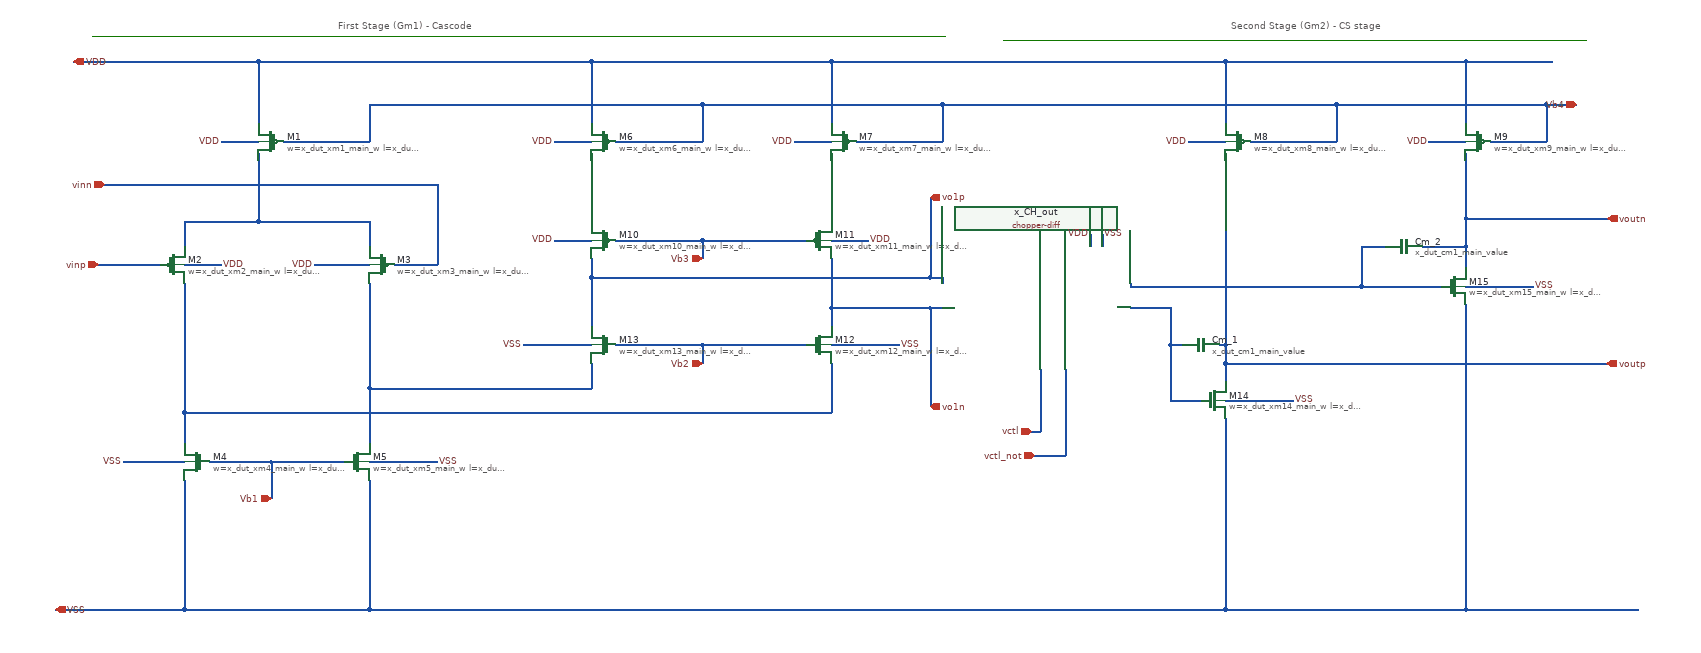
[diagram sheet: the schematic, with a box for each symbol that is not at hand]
v {xschem version=3.4.5 file_version=1.2
}
G {}
K {}
V {}
S {}
E {}
L 4 1600 -1055 2545 -1055 {}
L 4 120 -1060 1505 -1060 {}
T {First Stage (Gm1) - Cascode} 520 -1090 0 0 0.4 0.4 {}
T {Second Stage (Gm2) - CS stage} 1970 -1090 0 0 0.4 0.4 {}
N 270 -760 390 -760 {
lab=#net1}
N 270 -760 270 -720 {
lab=#net1}
N 390 -760 570 -760 {
lab=#net1}
N 570 -760 570 -720 {
lab=#net1}
N 390 -870 390 -760 {
lab=#net1}
N 610 -690 680 -690 {
lab=vinn}
N 680 -820 680 -690 {
lab=vinn}
N 140 -820 680 -820 {
lab=vinn}
N 130 -690 230 -690 {
lab=vinp}
N 270 -690 330 -690 {
lab=VDD}
N 480 -690 570 -690 {
lab=VDD}
N 330 -890 390 -890 {
lab=VDD}
N 430 -890 570 -890 {
lab=Vb4}
N 1320 -1020 1960 -1020 {
lab=VDD}
N 2350 -130 2630 -130 {
lab=VSS}
N 270 -450 270 -400 {
lab=#net2}
N 390 -1020 390 -920 {
lab=VDD}
N 90 -1020 390 -1020 {
lab=VDD}
N 570 -490 570 -400 {
lab=#net3}
N 410 -370 530 -370 {
lab=Vb1}
N 270 -340 270 -130 {
lab=VSS}
N 60 -130 270 -130 {
lab=VSS}
N 570 -340 570 -130 {
lab=VSS}
N 270 -130 570 -130 {
lab=VSS}
N 170 -370 270 -370 {
lab=VSS}
N 570 -370 680 -370 {
lab=VSS}
N 930 -870 930 -760 {
lab=#net4}
N 870 -890 930 -890 {
lab=VDD}
N 970 -890 1110 -890 {
lab=Vb4}
N 930 -1020 930 -920 {
lab=VDD}
N 390 -1020 930 -1020 {
lab=VDD}
N 1320 -870 1320 -760 {
lab=#net5}
N 1260 -890 1320 -890 {
lab=VDD}
N 1360 -890 1500 -890 {
lab=Vb4}
N 1320 -1020 1320 -920 {
lab=VDD}
N 930 -1020 1320 -1020 {
lab=VDD}
N 1960 -530 1960 -500 {
lab=voutp}
N 1900 -890 1960 -890 {
lab=VDD}
N 2000 -890 2140 -890 {
lab=Vb4}
N 1960 -1020 1960 -920 {
lab=VDD}
N 2290 -890 2350 -890 {
lab=VDD}
N 2480 -950 2530 -950 {
lab=Vb4}
N 2350 -1020 2350 -920 {
lab=VDD}
N 1960 -1020 2350 -1020 {
lab=VDD}
N 2350 -1020 2490 -1020 {
lab=VDD}
N 2480 -950 2480 -890 {
lab=Vb4}
N 2390 -890 2480 -890 {
lab=Vb4}
N 2140 -950 2480 -950 {
lab=Vb4}
N 2140 -950 2140 -890 {
lab=Vb4}
N 1500 -950 2140 -950 {
lab=Vb4}
N 1500 -950 1500 -890 {
lab=Vb4}
N 1110 -950 1500 -950 {
lab=Vb4}
N 1110 -950 1110 -890 {
lab=Vb4}
N 570 -950 1110 -950 {
lab=Vb4}
N 570 -950 570 -890 {
lab=Vb4}
N 870 -730 930 -730 {
lab=VDD}
N 1320 -730 1380 -730 {
lab=VDD}
N 1110 -730 1280 -730 {
lab=Vb3}
N 1320 -560 1430 -560 {
lab=VSS}
N 820 -560 930 -560 {
lab=VSS}
N 1320 -620 1320 -590 {
lab=vo1n}
N 930 -670 930 -590 {
lab=VDD}
N 1110 -560 1280 -560 {
lab=Vb2}
N 1320 -530 1320 -450 {
lab=#net2}
N 270 -450 1320 -450 {
lab=#net2}
N 270 -660 270 -450 {
lab=#net2}
N 930 -530 930 -490 {
lab=#net3}
N 570 -490 930 -490 {
lab=#net3}
N 570 -660 570 -490 {
lab=#net3}
N 410 -370 410 -310 {
lab=Vb1}
N 310 -370 410 -370 {
lab=Vb1}
N 1110 -560 1110 -530 {
lab=Vb2}
N 970 -560 1110 -560 {
lab=Vb2}
N 1110 -730 1110 -700 {
lab=Vb3}
N 970 -730 1110 -730 {
lab=Vb3}
N 1480 -620 1500 -620 {
lab=vo1n}
N 1320 -700 1320 -620 {
lab=vo1n}
N 1480 -670 1500 -670 {
lab=VDD}
N 930 -700 930 -670 {
lab=VDD}
N 1960 -470 2070 -470 {
lab=VSS}
N 2350 -655 2460 -655 {
lab=VSS}
N 1960 -130 2350 -130 {
lab=VSS}
N 1960 -440 1960 -130 {
lab=VSS}
N 570 -130 1960 -130 {
lab=VSS}
N 1870 -470 1920 -470 {
lab=#net6}
N 1870 -560 1870 -470 {
lab=#net6}
N 1805 -620 1870 -620 {
lab=#net6}
N 1870 -560 1890 -560 {
lab=#net6}
N 1870 -620 1870 -560 {
lab=#net6}
N 1950 -560 1960 -560 {
lab=voutp}
N 1960 -870 1960 -560 {
lab=voutp}
N 1805 -655 2180 -655 {
lab=#net7}
N 2180 -720 2180 -655 {
lab=#net7}
N 2180 -655 2310 -655 {
lab=#net7}
N 2180 -720 2220 -720 {
lab=#net7}
N 2280 -720 2350 -720 {
lab=voutn}
N 2350 -765 2350 -720 {
lab=voutn}
N 2350 -765 2580 -765 {
lab=voutn}
N 1960 -530 2580 -530 {
lab=voutp}
N 1960 -560 1960 -530 {
lab=voutp}
N 1500 -670 1500 -660 {
lab=VDD}
N 1805 -660 1805 -655 {
lab=#net7}
N 1660 -520 1660 -420 {
lab=vctl}
N 1645 -420 1660 -420 {
lab=vctl}
N 1650 -380 1700 -380 {
lab=vctl_not}
N 1700 -520 1700 -380 {
lab=vctl_not}
N 1740 -740 1740 -720 {
lab=VDD}
N 1760 -720 1760 -740 {
lab=VSS}
N 2350 -870 2350 -765 {
lab=voutn}
N 2350 -720 2350 -685 {
lab=voutn}
N 2350 -625 2350 -130 {
lab=VSS}
N 930 -670 1480 -670 {
lab=VDD}
N 1480 -620 1480 -460 {
lab=vo1n}
N 1320 -620 1480 -620 {
lab=vo1n}
N 1480 -800 1480 -670 {
lab=VDD}
C {devices/title.sym} 190 -70 0 0 {name=l5 author="Copyright 2026 MacAnalog Research Group"}
C {iopin.sym} 90 -1020 0 1 {name=p1 lab=VDD}
C {iopin.sym} 60 -130 0 1 {name=p5 lab=VSS}
C {sg13g2_pr/sg13_lv_pmos.sym} 410 -890 0 1 {name=M1
l=x_dut_xm1_main_l
w=x_dut_xm1_main_w
ng=1
m=1
model=sg13_lv_pmos
spiceprefix=X
}
C {sg13g2_pr/sg13_lv_pmos.sym} 250 -690 0 0 {name=M2
l=x_dut_xm2_main_l
w=x_dut_xm2_main_w
ng=1
m=1
model=sg13_lv_pmos
spiceprefix=X
}
C {sg13g2_pr/sg13_lv_pmos.sym} 590 -690 0 1 {name=M3
l=x_dut_xm3_main_l
w=x_dut_xm3_main_w
ng=1
m=1
model=sg13_lv_pmos
spiceprefix=X
}
C {iopin.sym} 2530 -950 0 0 {name=p2 lab=Vb4}
C {ipin.sym} 130 -690 0 0 {name=p3 lab=vinp}
C {ipin.sym} 140 -820 0 0 {name=p4 lab=vinn}
C {lab_pin.sym} 330 -690 0 1 {name=p8 sig_type=std_logic lab=VDD}
C {lab_pin.sym} 480 -690 0 0 {name=p9 sig_type=std_logic lab=VDD}
C {lab_pin.sym} 330 -890 0 0 {name=p10 sig_type=std_logic lab=VDD}
C {sg13g2_pr/sg13_lv_nmos.sym} 290 -370 0 1 {name=M4
l=x_dut_xm4_main_l
w=x_dut_xm4_main_w
ng=1
m=1
model=sg13_lv_nmos
spiceprefix=X
}
C {sg13g2_pr/sg13_lv_nmos.sym} 550 -370 0 0 {name=M5
l=x_dut_xm5_main_l
w=x_dut_xm5_main_w
ng=1
m=1
model=sg13_lv_nmos
spiceprefix=X
}
C {lab_pin.sym} 680 -370 0 1 {name=p6 sig_type=std_logic lab=VSS}
C {lab_pin.sym} 170 -370 0 0 {name=p7 sig_type=std_logic lab=VSS}
C {sg13g2_pr/sg13_lv_pmos.sym} 950 -890 0 1 {name=M6
l=x_dut_xm6_main_l
w=x_dut_xm6_main_w
ng=1
m=1
model=sg13_lv_pmos
spiceprefix=X
}
C {lab_pin.sym} 870 -890 0 0 {name=p11 sig_type=std_logic lab=VDD}
C {sg13g2_pr/sg13_lv_pmos.sym} 1340 -890 0 1 {name=M7
l=x_dut_xm7_main_l
w=x_dut_xm7_main_w
ng=1
m=1
model=sg13_lv_pmos
spiceprefix=X
}
C {lab_pin.sym} 1260 -890 0 0 {name=p12 sig_type=std_logic lab=VDD}
C {sg13g2_pr/sg13_lv_pmos.sym} 1980 -890 0 1 {name=M8
l=x_dut_xm8_main_l
w=x_dut_xm8_main_w
ng=1
m=1
model=sg13_lv_pmos
spiceprefix=X
}
C {lab_pin.sym} 1900 -890 0 0 {name=p13 sig_type=std_logic lab=VDD}
C {sg13g2_pr/sg13_lv_pmos.sym} 2370 -890 0 1 {name=M9
l=x_dut_xm9_main_l
w=x_dut_xm9_main_w
ng=1
m=1
model=sg13_lv_pmos
spiceprefix=X
}
C {lab_pin.sym} 2290 -890 0 0 {name=p14 sig_type=std_logic lab=VDD}
C {sg13g2_pr/sg13_lv_pmos.sym} 950 -730 0 1 {name=M10
l=x_dut_xm10_main_l
w=x_dut_xm10_main_w
ng=1
m=1
model=sg13_lv_pmos
spiceprefix=X
}
C {lab_pin.sym} 870 -730 0 0 {name=p15 sig_type=std_logic lab=VDD}
C {sg13g2_pr/sg13_lv_pmos.sym} 1300 -730 0 0 {name=M11
l=x_dut_xm11_main_l
w=x_dut_xm11_main_w
ng=1
m=1
model=sg13_lv_pmos
spiceprefix=X
}
C {lab_pin.sym} 1380 -730 0 1 {name=p16 sig_type=std_logic lab=VDD}
C {sg13g2_pr/sg13_lv_nmos.sym} 1300 -560 0 0 {name=M12
l=x_dut_xm12_main_l
w=x_dut_xm12_main_w
ng=1
m=1
model=sg13_lv_nmos
spiceprefix=X
}
C {lab_pin.sym} 1430 -560 0 1 {name=p17 sig_type=std_logic lab=VSS}
C {sg13g2_pr/sg13_lv_nmos.sym} 950 -560 0 1 {name=M13
l=x_dut_xm13_main_l
w=x_dut_xm13_main_w
ng=1
m=1
model=sg13_lv_nmos
spiceprefix=X
}
C {lab_pin.sym} 820 -560 0 0 {name=p18 sig_type=std_logic lab=VSS}
C {iopin.sym} 1110 -700 0 0 {name=p19 lab=Vb3}
C {iopin.sym} 1110 -530 0 0 {name=p20 lab=Vb2}
C {iopin.sym} 410 -310 0 0 {name=p21 lab=Vb1}
C {shared/chopper-diff.sym} 1520 -540 0 0 {name=x_CH_out}
C {sg13g2_pr/sg13_lv_nmos.sym} 1940 -470 0 0 {name=M14
l=x_dut_xm14_main_l
w=x_dut_xm14_main_w
ng=1
m=1
model=sg13_lv_nmos
spiceprefix=X
}
C {lab_pin.sym} 2070 -470 0 1 {name=p22 sig_type=std_logic lab=VSS}
C {sg13g2_pr/sg13_lv_nmos.sym} 2330 -655 0 0 {name=M15
l=x_dut_xm15_main_l
w=x_dut_xm15_main_w
ng=1
m=1
model=sg13_lv_nmos
spiceprefix=X
}
C {lab_pin.sym} 2460 -655 0 1 {name=p23 sig_type=std_logic lab=VSS}
C {capa.sym} 1920 -560 3 0 {name=Cm_1
m=1
value=x_dut_cm1_main_value
footprint=1206
device="ceramic capacitor"}
C {lab_pin.sym} 1740 -740 0 0 {name=p24 sig_type=std_logic lab=VDD}
C {lab_pin.sym} 1760 -740 0 1 {name=p25 sig_type=std_logic lab=VSS}
C {capa.sym} 2250 -720 3 0 {name=Cm_2
m=1
value=x_dut_cm1_main_value
footprint=1206
device="ceramic capacitor"}
C {opin.sym} 2580 -765 0 0 {name=p26 lab=voutn}
C {opin.sym} 2578.75 -530 0 0 {name=p27 lab=voutp}
C {ipin.sym} 1650 -380 0 0 {name=p28 lab=vctl_not}
C {ipin.sym} 1645 -420 0 0 {name=p29 lab=vctl}
C {iopin.sym} 1480 -800 0 1 {name=p30 lab=vo1p}
C {iopin.sym} 1480 -460 0 1 {name=p31 lab=vo1n}
